! (c) 2009  Infineon Technologies AG, Munich
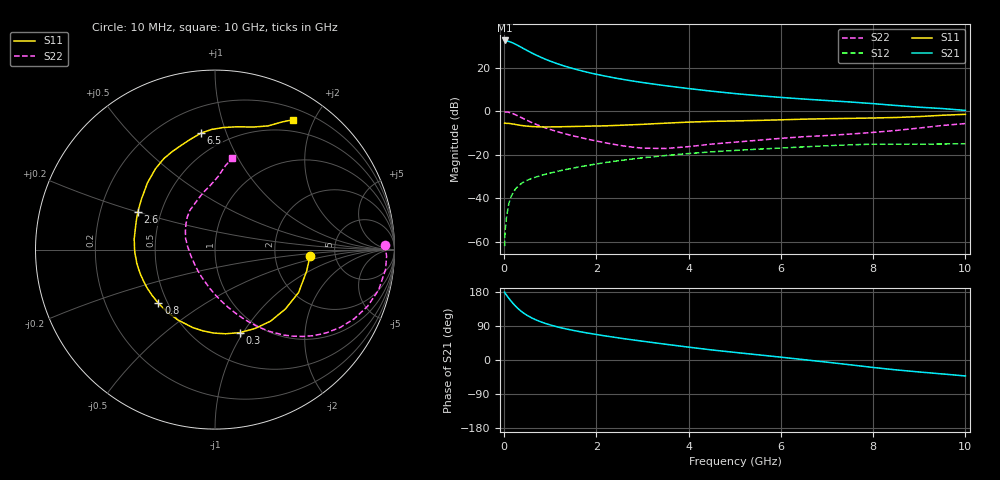
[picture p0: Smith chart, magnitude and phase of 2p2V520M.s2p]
! Infineon Technologies  Discrete & RF Semiconductors
! BFP420
! VCE =  2.5 V,  IC =  20 mA
! Common Emitter S-Parameters:  Nov 2009
# GHz  S  MA  R  50
!  f  S11  S21  S12  S22
! GHz  MAG  ANG  MAG  ANG  MAG  ANG  MAG  ANG
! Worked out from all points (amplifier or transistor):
!   46 points, 10 MHz to 10 GHz, reference 50 ohm
!   highest |S21| = 32.4 dB at 10 MHz (marker M1)
!   |S21| within 3 dB of that: start of sweep to 359.7 MHz
!   unconditionally stable (mu >= 1): start of sweep to 11.26 MHz; 1.81 GHz to end of sweep
!   at 300 MHz: K = 0.31, MSG = 32.3 dB, |S12| = -34.5 dB
!   at 1.7 GHz: K = 0.97, MSG = 21.8 dB, |S12| = -25.3 dB
!   at 10 GHz: K = 1.07, MAG = 6.1 dB, |S12| = -15.0 dB
!   lowest NFmin = 1.23 dB at 900 MHz
!   S11 on the Smith chart (normalised r, x): 10 MHz: 3.23, -0.33; 300 MHz: 0.80, -0.97; 800 MHz: 0.45, -0.33; 2.6 GHz: 0.37, +0.20; 6.5 GHz: 0.36, +0.82; 10 GHz: 0.34, +1.72
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0.01  0.5311 -4.0  41.71 179.1  0.0008 85.6  0.9459 1.7
0.02  0.5286 -5.3  40.81 176.4  0.0018 90.0  0.9569 -2.2
0.05  0.5246 -13.2  40.48 171.4  0.0036 84.8  0.9568 -6.6
0.1  0.5235 -27.1  39.64 163.2  0.0075 78.9  0.9392 -13.8
0.15  0.5132 -40.1  38.05 155.4  0.0109 75.4  0.9068 -20.4
0.2  0.5049 -52.1  36.16 148.3  0.0139 70.9  0.8663 -26.4
0.25  0.4929 -63.1  33.99 141.7  0.0166 67.5  0.8218 -31.8
0.3  0.4827 -73.5  31.96 135.8  0.0189 64.6  0.7754 -36.7
0.4  0.4649 -91.2  27.97 125.8  0.0229 60.0  0.6878 -44.7
0.5  0.4517 -105.8  24.47 117.7  0.026 57.1  0.6109 -51.2
0.6  0.4434 -118.0  21.54 110.9  0.0287 55.2  0.5467 -56.4
0.8  0.4346 -136.6  17.08 100.5  0.0334 53.5  0.4487 -64.6
1  0.4345 -150.5  14 92.5  0.038 52.7  0.3789 -71.4
1.2  0.4374 -161.2  11.76 86.0  0.0426 52.3  0.327 -77.5
1.7  0.4486 179.0  8.287 73.5  0.0543 50.9  0.2412 -91.9
2.6  0.478 154.0  5.285 56.2  0.0756 45.5  0.1584 -123.4
3.5  0.5291 135.3  3.821 41.6  0.0959 38.2  0.139 -165.8
5.5  0.6112 107.8  2.267 13.8  0.1339 20.5  0.2146 139.0
6.5  0.6538 96.8  1.89 0.9  0.1513 11.6  0.2592 122.9
7  0.6699 91.6  1.747 -5.8  0.1605 6.9  0.2754 115.2
8.5  0.7146 72.8  1.346 -26.1  0.1746 -10.0  0.3602 93.9
10  0.8439 59.0  1.038 -42.1  0.1781 -21.1  0.5186 79.6
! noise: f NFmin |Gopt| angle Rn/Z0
0.9  1.23  0.16  -154  0.13
1.8  1.51  0.24  -144  0.13
2.4  1.66  0.22  -141  0.15
3  1.69  0.3  -132  0.16
4  1.82  0.42  -115  0.23
5  2.28  0.48  -96  0.37
6  2.65  0.52  -86  0.56
